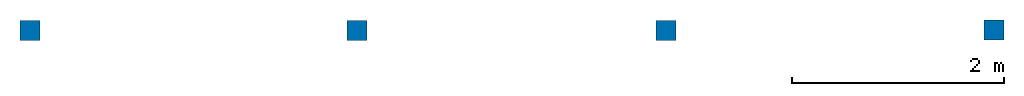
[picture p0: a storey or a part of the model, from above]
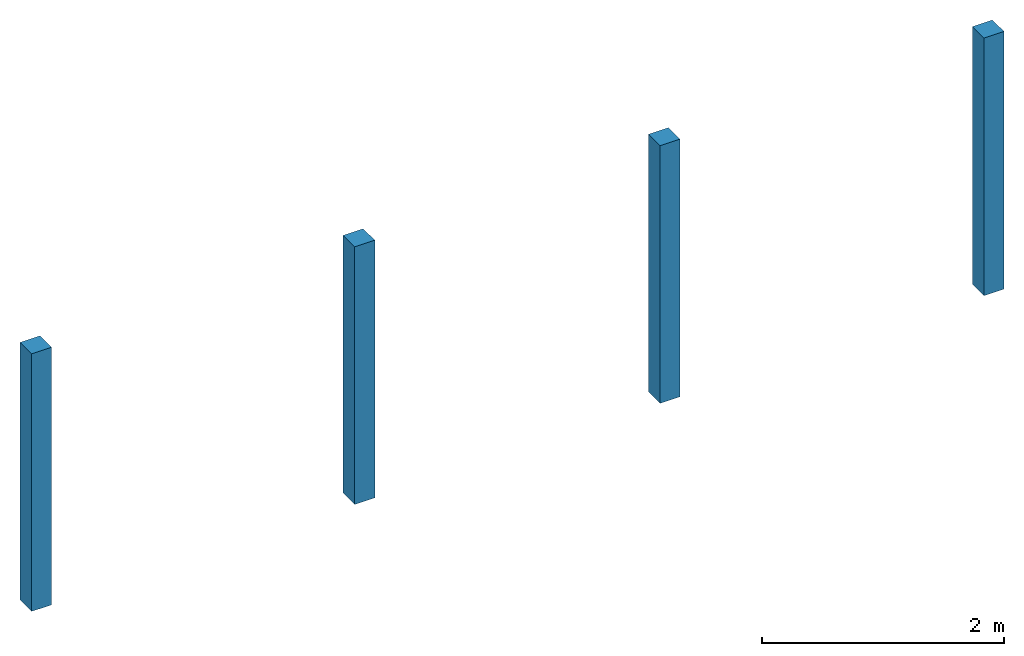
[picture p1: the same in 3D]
Properties of the parts of a building model (IFC2X3)

# File
Description: ViewDefinition [CoordinationView]
File name: Numéro du projet
Time: 2015-10-29T21:46:43
Written by: The EXPRESS Data Manager Version 5.02.0100.07 : 28 Aug 2013
Made in: 20140606_1530(x64) - Exporter 2015.0.2014.0606 - Default UI
Comment: STEP Physical File produced by: The EXPRESS Data Manager Version 5.02.0100.07 : 28 Aug 2013 * Module: EDMstepFileFactory/EDMstandAlone * Creation date: Thu Oct 29 21:46:43 2015 * Host: NI * Database: C:\Users\nicolas\AppData\Local\Temp\{D9AE8AF2-0353-474C-A98F-6EF9595D0228}\ifc * Database version: 5507 * Database creation date: Thu Oct 29 21:46:33 2015 * Schema: IFC2X3 * Model: DataRepository.ifc * Model creation date: Thu Oct 29 21:46:33 2015 * Header model: DataRepository.ifc_HeaderModel * Header model creation date: Thu Oct 29 21:46:33 2015 * EDMuser: sdai-user * EDMgroup: sdai-group * License ID and type: 5605 : Permanent license. Expiry date: * EDMstepFileFactory options: 020000

# IfcProject, Numéro du projet
LongName: Nom du projet; Phase: Etat du projet

# IfcSite, Default
RefLatitude: 48, 51, 23, 999633; RefLongitude: 2, 21, 3, 553905; RefElevation: 0 m
Autre - Adresse du projet: Entrer l'adresse ici; Catégorie: Informations sur le projet; Date de fin du projet: Date de fin; Etat du projet: Etat du projet; Nom du client: Propriétaire; Nom du projet: Nom du projet; Numéro de projet: Numéro du projet

# IfcBuilding
Pset_BuildingCommon - NumberOfStoreys: 3
Autre - Catégorie: Informations sur le projet; Adresse du projet: Entrer l'adresse ici; Date de fin du projet: Date de fin; Etat du projet: Etat du projet; Nom du client: Propriétaire; Nom du projet: Nom du projet; Numéro de projet: Numéro du projet

# IfcBuildingStorey (3)
Graphismes - Couleur: 12632256; Epaisseur des lignes: 1; Motif des lignes: Tiret point; Symbole: Marqueur de niveau - Point triangulaire: Marqueur de niveau - Point triangulaire; Valeur par défaut du symbole à l'extrémité 1: no; Valeur par défaut du symbole à l'extrémité 2: yes
Données d'identification - Nom du type: Ligne du Niveau; Etage de bâtiment: yes; Structure: no
Contraintes - Base de l'élévation: Point de base du projet
Autre - Catégorie: Niveaux; Nom de la famille: Niveau; Famille: Niveau: Ligne du Niveau; Famille et type: Niveau: Ligne du Niveau; ID du type: Niveau: Ligne du Niveau; Type: Niveau: Ligne du Niveau
Cotes - Hauteur de calcul: 0 m
Name | LongName = Nom | Elevation (m) = Elévation (m)
2 - RdC | 2 - RdC | 3
1 - Arase sup GC | 1 - Arase sup GC | 3.9
0 - Sabliere | 0 - Sabliere | 5.6

# IfcBeam: Poutre - Bois d'oeuvre:184x235:255924 (5)
In: 0 - Sabliere
Material: Bois - Bois de construction de dimensions courantes
Pset_BeamCommon - IsExternal: no; Slope: 0 deg; Reference: 184x235; LoadBearing: yes
Autre - Catégorie: Ossature; Famille: Poutre - Bois d'oeuvre: 184x235; Famille et type: Poutre - Bois d'oeuvre: 184x235; ID du type: Poutre - Bois d'oeuvre: 184x235; Type: Poutre - Bois d'oeuvre: 184x235; Nom de la famille: Poutre - Bois d'oeuvre
Contraintes - Orientation: Normale; Rotation de la section: 0 deg
Matériaux et finitions - Matériau structurel: Bois - Bois de construction de dimensions courantes
Phase de construction - Phase de création: Nouvelle construction
Position géométrique - Etat de la jonction: Deux jonctions activées; Extension de départ: 0 m; Extension de fin: 0 m; Justification Y: Origine; Justification YZ: Uniforme; Justification Z: Haut; Valeur de décalage Y: 0 m; Valeur de décalage Z: 0 m
Structure - Activer le modèle analytique: yes; Emplacement du symbole filaire: Centre de la géométrie; Utilisation structurelle: Poutrelle; A: 0.046 m2; Forme de coupe: 0
Cotes - b: 0.1905 m; d: 0.2413 m
Données d'identification - Nom du type: 184x235
Name (Poutre - Bois d'oeuvre:184x235:...) | Span (m) = Longueur (m) | ID hôte | Décalage du niveau d'arrivée (m) = Décalage du niveau de départ (m) | Niveau de référence | Plan de construction | Volume (m3) | Longueur de coupe (m)
256614 | 3.064 | Réseau de poutres: poutre bois | 0 | Niveau: 0 - Sabliere | Niveau : 0 - Sabliere | 0.140845 | 3.064
256763 | 3.418 | Réseau de poutres: poutre bois | 6.2 | Niveau: 4 - Fondations | <non associé> | 0.157117 | 3.418
258238 | 12.219 | Réseau de poutres: Système de poutre - Intervalle fixe 2 m | 0 | Niveau: 0 - Sabliere | Niveau : 0 - Sabliere | 0.561679 | 12.219
258409 | 6.495 | Réseau de poutres: Système de poutre - Intervalle fixe 2 m | 0 | Niveau: 0 - Sabliere | Niveau : 0 - Sabliere | 0.29856 | 6.495
258793 | 12.115 | Réseau de poutres: Système de poutre - Intervalle fixe 2 m | 0 | Niveau: 0 - Sabliere | Niveau : 0 - Sabliere | 0.552485 | 12.019 | Position géométrique - Réduction du joint d'extrémité: 0 m

# IfcColumn: 191 x 191mm (16)
Type - ElementType: 191 x 191mm; PredefinedType: COLUMN; Material: Bois - Bois de construction de dimensions courantes
Type - Autre - Catégorie: Poteaux; Nom de la famille: Poteau Bois
Type - Cotes - Largeur: 0.191 m; Profondeur: 0.191 m
Type - Données d'identification - Nom du type: 191 x 191mm
Type - Graphismes - Couleur vue détail faible: 0
Type - Matériaux et finitions - Matériau: Bois - Bois de construction de dimensions courantes
Pset_ColumnCommon - Reference: 191 x 191mm; LoadBearing: no; IsExternal: no
Autre - Famille: Poteau Bois: 191 x 191mm; Famille et type: Poteau Bois: 191 x 191mm; ID du type: Poteau Bois: 191 x 191mm; Type: Poteau Bois: 191 x 191mm
Contraintes - Décalage inférieur: 0 m; Décalage supérieur: 0 m; Limite de pièce: yes; Niveau supérieur: Niveau: 0 - Sabliere; Se déplace avec les quadrillages: yes
Phase de construction - Phase de création: Nouvelle construction
Name (Poteau Bois:191 x 191mm:...) | In | Niveau = Niveau de base | Surface (m2) | Volume (m3)
250008 | 1 - Arase sup GC | Niveau: 1 - Arase sup GC | 0.685881 | 0.0620177 | Pset_ColumnCommon - Slope: 0 deg
250188 | 1 - Arase sup GC | Niveau: 1 - Arase sup GC | 0.685881 | 0.0620177
250301 | 1 - Arase sup GC | Niveau: 1 - Arase sup GC | 0.685881 | 0.0620177
250442 | 1 - Arase sup GC | Niveau: 1 - Arase sup GC | 0.685881 | 0.0620177
250726 | 1 - Arase sup GC | Niveau: 1 - Arase sup GC | 0.685881 | 0.0620177
250813 | 1 - Arase sup GC | Niveau: 1 - Arase sup GC | 0.685881 | 0.0620177
250973 | 1 - Arase sup GC | Niveau: 1 - Arase sup GC | 0.685881 | 0.0620177
251070 | 1 - Arase sup GC | Niveau: 1 - Arase sup GC | 0.685881 | 0.0620177
251283 | 1 - Arase sup GC | Niveau: 1 - Arase sup GC | 0.685881 | 0.0620177
251511 | 1 - Arase sup GC | Niveau: 1 - Arase sup GC | 0.685881 | 0.0620177
252161 | 1 - Arase sup GC | Niveau: 1 - Arase sup GC | 0.685881 | 0.0620177
252440 | 1 - Arase sup GC | Niveau: 1 - Arase sup GC | 0.685881 | 0.0620177
252587 | 2 - RdC | Niveau: 2 - RdC | 1.02968 | 0.0948506 | Pset_ColumnCommon - Slope: 0 deg
252882 | 2 - RdC | Niveau: 2 - RdC | 1.02968 | 0.0948506
253012 | 2 - RdC | Niveau: 2 - RdC | 1.02968 | 0.0948506
253079 | 2 - RdC | Niveau: 2 - RdC | 1.02968 | 0.0948506

# IfcElementAssembly: Réseau de poutres:Système de poutre - Intervalle fixe 2 m (3)
In: 0 - Sabliere
PredefinedType: BEAM_GRID
Données d'identification - Nom du type: Système de poutre - Intervalle fixe 2 m; Etiqueter les nouveaux membres dans la vue: Plan d'étage: 0 - Sabliere
Autre - Catégorie: Réseaux de poutres; Famille: Réseau de poutres: Système de poutre - Intervalle fixe 2 m; Famille et type: Réseau de poutres: Système de poutre - Intervalle fixe 2 m; ID du type: Réseau de poutres: Système de poutre - Intervalle fixe 2 m; Type: Réseau de poutres: Système de poutre - Intervalle fixe 2 m; Nom de la famille: Réseau de poutres
Contraintes - 3D: no; Elévation: 0 m; Plan de construction: Niveau : 0 - Sabliere
Motif - Espacement de l'axe: 1.8288 m; Espacement fixe: 1.8288 m; Justification: Centre; Règle de présentation: Distance fixe; Type de poutre: Poutre - Bois d'oeuvre: 184x235; Type de poutre (aucun nom de famille): Poutre - Bois d'oeuvre: 184x235
Phase de construction - Phase de création: Nouvelle construction
Name (Réseau de poutres:Système de poutre - Intervalle fixe 2 m:...)
258018
258251
258420

# IfcElementAssembly: Réseau de poutres:poutre bois (2)
In: 0 - Sabliere
PredefinedType: BEAM_GRID
Autre - Catégorie: Réseaux de poutres; Famille: Réseau de poutres: poutre bois; Famille et type: Réseau de poutres: poutre bois; ID du type: Réseau de poutres: poutre bois; Type: Réseau de poutres: poutre bois; Nom de la famille: Réseau de poutres
Contraintes - 3D: no; Elévation: 0 m
Motif - Espacement de l'axe: 1.8288 m; Espacement fixe: 1.8288 m; Justification: Centre; Règle de présentation: Distance fixe; Type de poutre: Poutre - Bois d'oeuvre: 184x235; Type de poutre (aucun nom de famille): Poutre - Bois d'oeuvre: 184x235
Phase de construction - Phase de création: Nouvelle construction
Données d'identification - Nom du type: poutre bois
Name (Réseau de poutres:poutre bois:...) | Plan de construction
253510 | Niveau : 0 - Sabliere | Données d'identification - Etiqueter les nouveaux membres dans la vue: Plan d'étage: 0 - Sabliere
256758 | <non associé>

# IfcRoof: Toit de base:Toit - 200 mm, Toit de base:Toit - 200 mm:259233
In: 0 - Sabliere
Pset_RoofCommon - Reference: Toit - 200 mm; IsExternal: yes; TotalArea: 91.7179 m2; ProjectedArea: 79.43 m2
Autre - Catégorie: Toits; Famille: Toit de base: Toit - 200 mm; Famille et type: Toit de base: Toit - 200 mm; ID du type: Toit de base: Toit - 200 mm; Type: Toit de base: Toit - 200 mm; Nom de la famille: Toit de base
Construction - Coupe en chevron: Coupe verticale; Hauteur maximale de l'arrête: 7.70733 m; Profondeur du bord de toiture: 0 m; Epaisseur par défaut: 0.2 m
Contraintes - Limite de pièce: yes; Décalage de la coupure: 0 m; Décalage inférieur à partir du niveau: 0 m; Lié au volume: no; Niveau de base: Niveau: 0 - Sabliere
Cotes - Epaisseur: 0.2 m; Inclinaison: 0.57735; Surface: 91.7179 m2; Volume: 18.3436 m3
Phase de construction - Phase de création: Nouvelle construction
Données d'identification - Nom du type: Toit - 200 mm
Graphismes - Couleur vue détail faible: 0
Propriétés analytiques - Coefficient d'absorbance: 0.7; Rugosité: 3

# IfcSlab: Toit de base:Toit - 200 mm (4)
In: 0 - Sabliere
PredefinedType: ROOF; Material: Toit par défaut 0.2 m
Pset_SlabCommon - LoadBearing: yes; Reference: Toit - 200 mm; IsExternal: yes; PitchAngle: 30 deg
